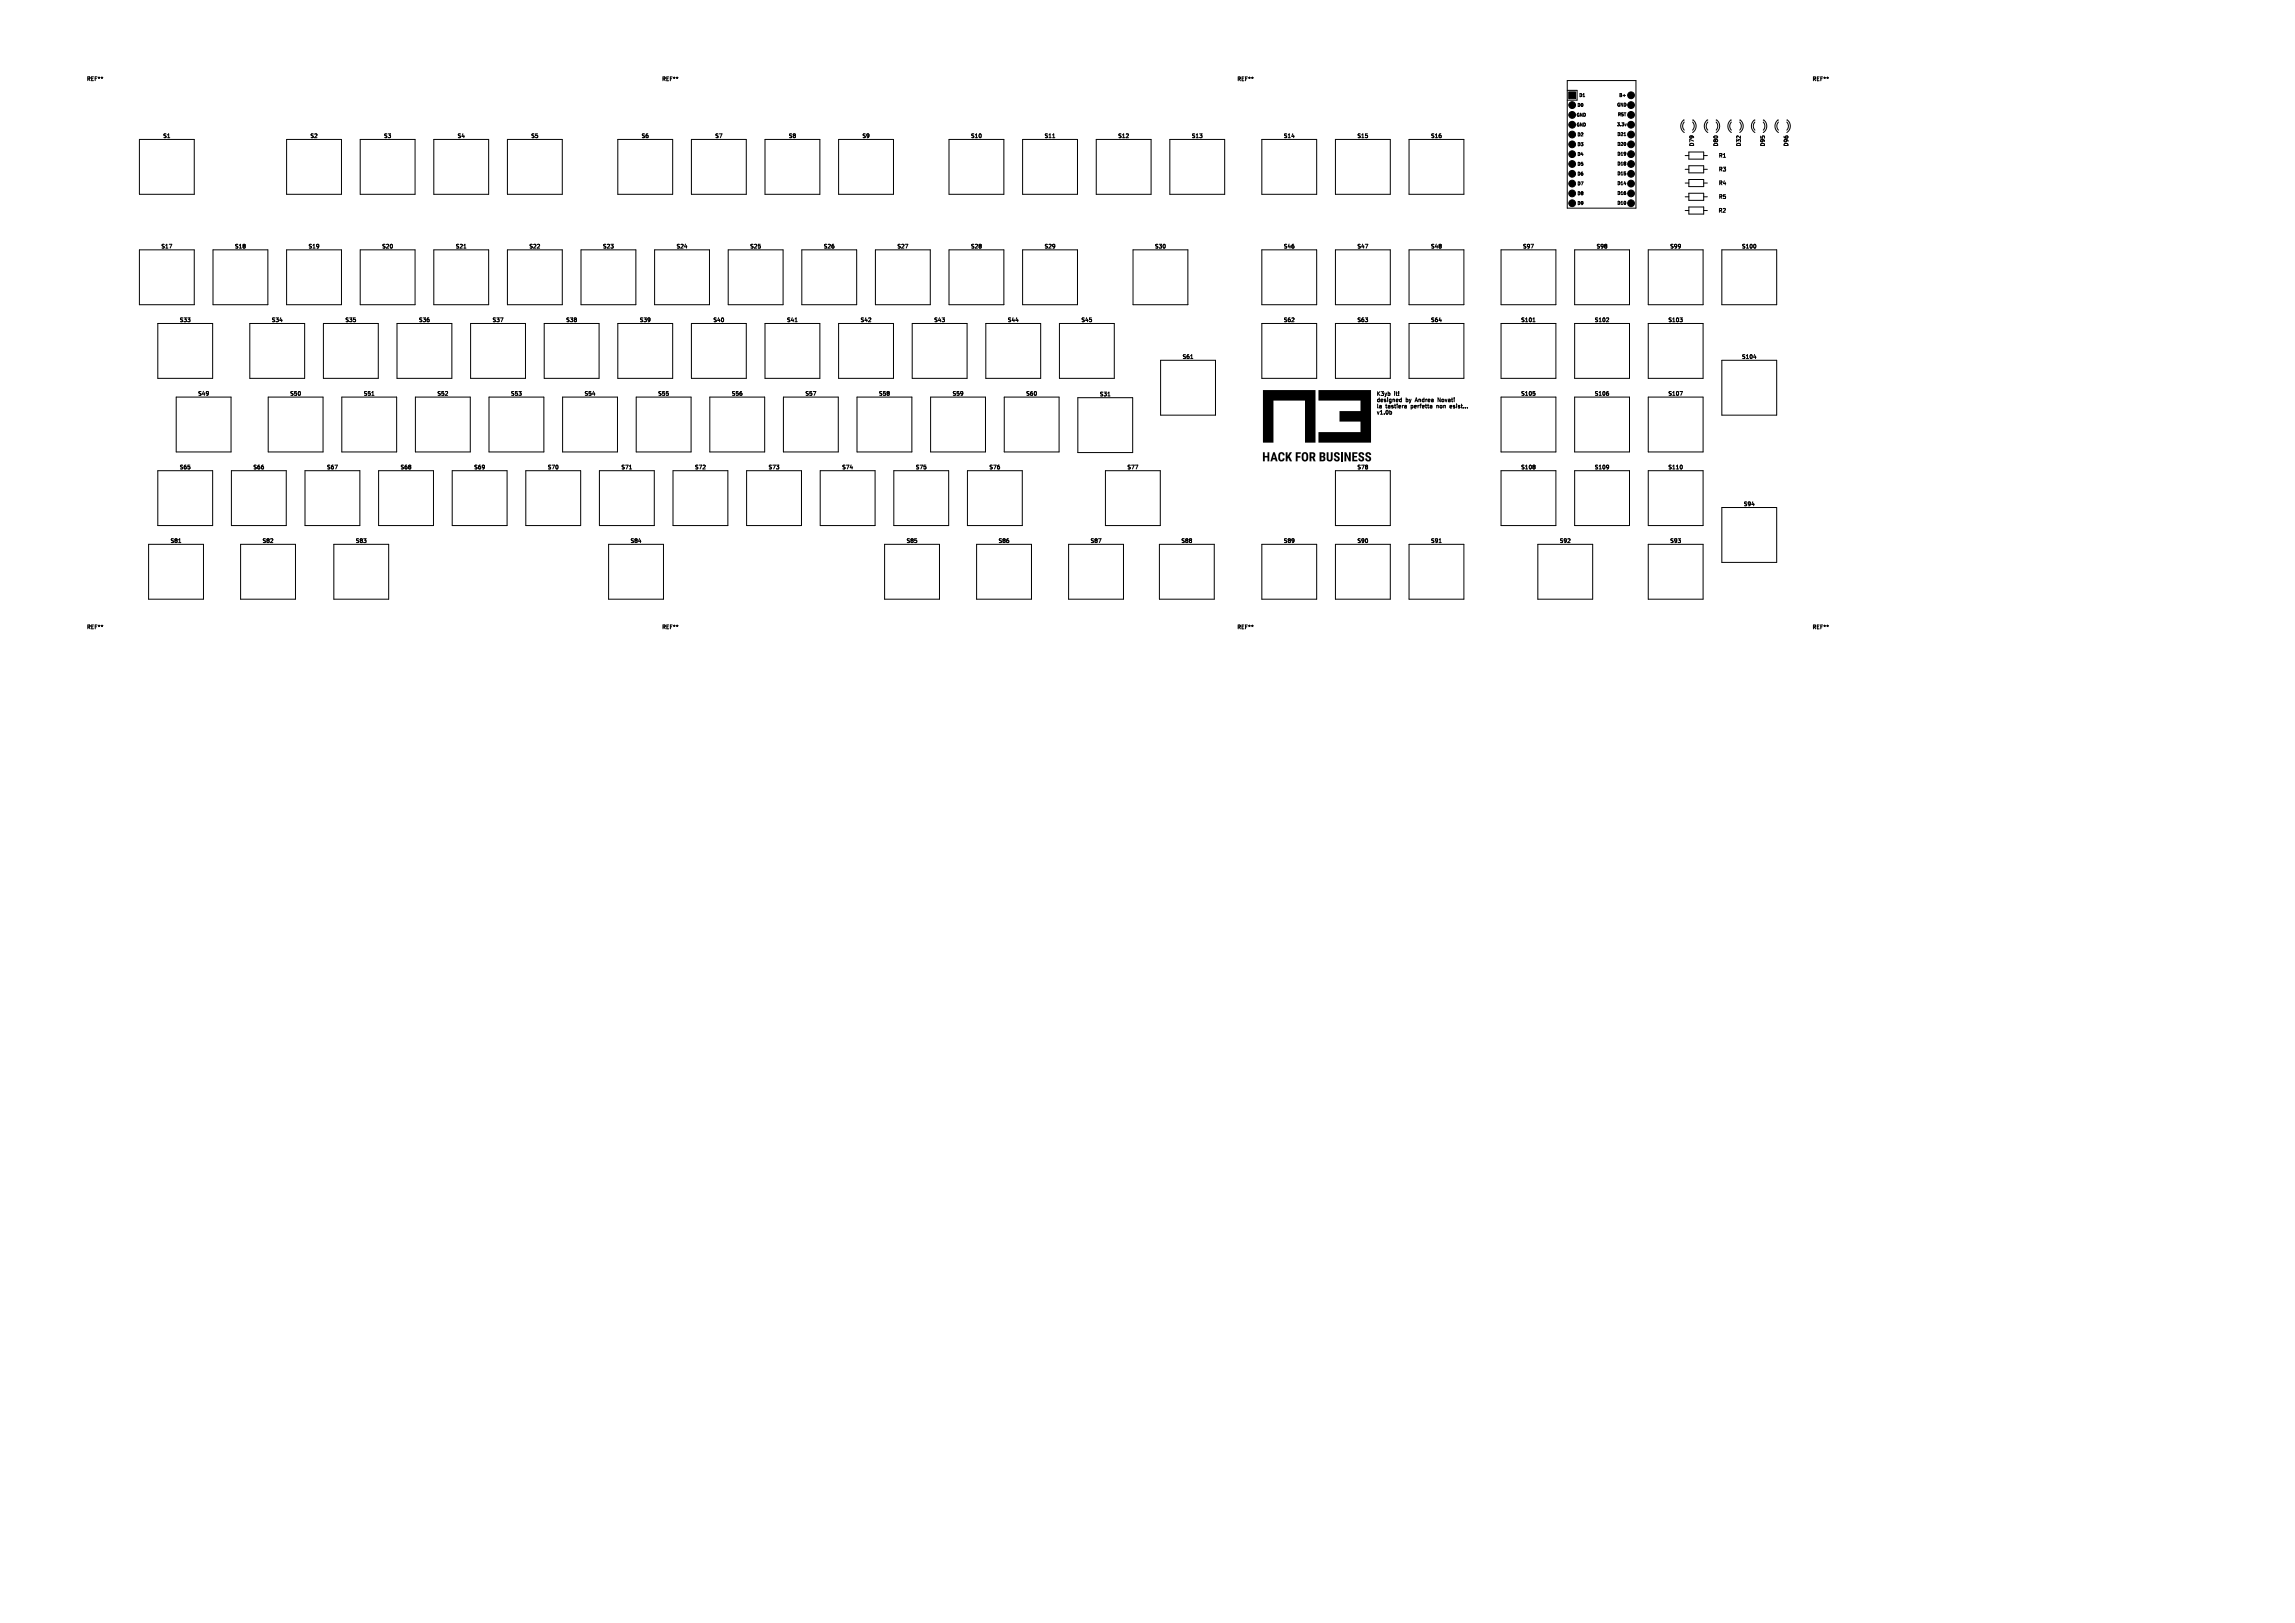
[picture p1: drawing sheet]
<svg xmlns="http://www.w3.org/2000/svg" width="594mm" height="420mm" viewBox="0 0 594 420" stroke-linecap="round" stroke-linejoin="round" font-family="sans-serif">
<defs><g id="words">
<g font-size="1.4">
<text x="22.4" y="21.2">REF**</text>
<text x="171.2" y="21.2">REF**</text>
<text x="320.1" y="21.2">REF**</text>
<text x="469" y="21.2">REF**</text>
<text x="42.1" y="35.9">S1</text>
<text x="80.2" y="35.9">S2</text>
<text x="99.3" y="35.9">S3</text>
<text x="118.3" y="35.9">S4</text>
<text x="137.4" y="35.9">S5</text>
<text x="165.9" y="35.9">S6</text>
<text x="185" y="35.9">S7</text>
<text x="204" y="35.9">S8</text>
<text x="223.1" y="35.9">S9</text>
<text x="251.2" y="35.9">S10</text>
<text x="270.2" y="35.9">S11</text>
<text x="289.3" y="35.9">S12</text>
<text x="308.3" y="35.9">S13</text>
<text x="332.1" y="35.9">S14</text>
<text x="351.2" y="35.9">S15</text>
<text x="370.2" y="35.9">S16</text>
<text x="438.6" y="38" transform="rotate(-90 438.6 38)">D79</text>
<text x="444.7" y="41">R1</text>
<text x="444.8" y="38" transform="rotate(-90 444.8 38)">D80</text>
<text x="450.7" y="38" transform="rotate(-90 450.7 38)">D32</text>
<text x="457" y="38" transform="rotate(-90 457 38)">D95</text>
<text x="463" y="38" transform="rotate(-90 463 38)">D96</text>
<text x="444.7" y="44.5">R3</text>
<text x="444.7" y="51.6">R5</text>
<text x="444.7" y="48.1">R4</text>
<text x="444.7" y="55.2">R2</text>
<text x="41.6" y="64.5">S17</text>
<text x="60.7" y="64.5">S18</text>
<text x="79.7" y="64.5">S19</text>
<text x="98.8" y="64.5">S20</text>
<text x="117.8" y="64.5">S21</text>
<text x="136.9" y="64.5">S22</text>
<text x="155.9" y="64.5">S23</text>
<text x="175" y="64.5">S24</text>
<text x="194" y="64.5">S25</text>
<text x="213.1" y="64.5">S26</text>
<text x="232.1" y="64.5">S27</text>
<text x="251.2" y="64.5">S28</text>
<text x="270.2" y="64.5">S29</text>
<text x="298.8" y="64.5">S30</text>
<text x="332.1" y="64.5">S46</text>
<text x="351.2" y="64.5">S47</text>
<text x="370.2" y="64.5">S48</text>
<text x="394.1" y="64.5">S97</text>
<text x="413.1" y="64.5">S98</text>
<text x="432.2" y="64.5">S99</text>
<text x="450.7" y="64.5">S100</text>
<text x="46.4" y="83.5">S33</text>
<text x="70.2" y="83.5">S34</text>
<text x="89.3" y="83.5">S35</text>
<text x="108.3" y="83.5">S36</text>
<text x="127.4" y="83.5">S37</text>
<text x="146.4" y="83.5">S38</text>
<text x="165.5" y="83.5">S39</text>
<text x="184.5" y="83.5">S40</text>
<text x="203.6" y="83.5">S41</text>
<text x="222.6" y="83.5">S42</text>
<text x="241.7" y="83.5">S43</text>
<text x="260.7" y="83.5">S44</text>
<text x="279.8" y="83.5">S45</text>
<text x="332.1" y="83.5">S62</text>
<text x="351.2" y="83.5">S63</text>
<text x="370.2" y="83.5">S64</text>
<text x="393.6" y="83.5">S101</text>
<text x="412.6" y="83.5">S102</text>
<text x="431.7" y="83.5">S103</text>
<text x="305.9" y="93.1">S61</text>
<text x="450.7" y="93.1">S104</text>
<text x="51.2" y="102.6">S49</text>
<text x="75" y="102.6">S50</text>
<text x="94" y="102.6">S51</text>
<text x="113.1" y="102.6">S52</text>
<text x="132.1" y="102.6">S53</text>
<text x="151.2" y="102.6">S54</text>
<text x="170.2" y="102.6">S55</text>
<text x="189.3" y="102.6">S56</text>
<text x="208.3" y="102.6">S57</text>
<text x="227.4" y="102.6">S58</text>
<text x="246.4" y="102.6">S59</text>
<text x="265.5" y="102.6">S60</text>
<text x="284.5" y="102.7">S31</text>
<text x="356.2" y="102.5">K3yb</text>
<text x="356.2" y="104.1">designed</text>
<text x="356.2" y="105.7">la</text>
<text x="356.2" y="107.3">v1.0b</text>
<text x="358.7" y="105.7">tastiera</text>
<text x="360.9" y="102.5">it!</text>
<text x="363.9" y="104.1">by</text>
<text x="365.4" y="105.7">perfetta</text>
<text x="366.5" y="104.1">Andrea</text>
<text x="372.3" y="105.7">non</text>
<text x="372.6" y="104.1">Novati</text>
<text x="376" y="105.7">esist...</text>
<text x="393.6" y="102.6">S105</text>
<text x="412.6" y="102.6">S106</text>
<text x="431.7" y="102.6">S107</text>
<text x="46.4" y="121.6">S65</text>
<text x="65.4" y="121.6">S66</text>
<text x="84.5" y="121.6">S67</text>
<text x="103.5" y="121.6">S68</text>
<text x="122.6" y="121.6">S69</text>
<text x="141.6" y="121.6">S70</text>
<text x="160.7" y="121.6">S71</text>
<text x="179.7" y="121.6">S72</text>
<text x="198.8" y="121.6">S73</text>
<text x="217.8" y="121.6">S74</text>
<text x="236.9" y="121.6">S75</text>
<text x="255.9" y="121.6">S76</text>
<text x="291.7" y="121.6">S77</text>
<text x="351.2" y="121.6">S78</text>
<text x="393.6" y="121.6">S108</text>
<text x="412.6" y="121.6">S109</text>
<text x="431.7" y="121.6">S110</text>
<text x="451.2" y="131.2">S94</text>
<text x="44" y="140.7">S81</text>
<text x="67.8" y="140.7">S82</text>
<text x="92" y="140.7">S83</text>
<text x="163.1" y="140.7">S84</text>
<text x="234.5" y="140.7">S85</text>
<text x="258.3" y="140.7">S86</text>
<text x="282.1" y="140.7">S87</text>
<text x="305.6" y="140.7">S88</text>
<text x="332.1" y="140.7">S89</text>
<text x="351.2" y="140.7">S90</text>
<text x="370.2" y="140.7">S91</text>
<text x="403.6" y="140.7">S92</text>
<text x="432.2" y="140.7">S93</text>
<text x="22.4" y="163">REF**</text>
<text x="171.2" y="163">REF**</text>
<text x="320.1" y="163">REF**</text>
<text x="469" y="163">REF**</text>
</g>
<g font-size="1.1">
<text x="408.1" y="27.8">D0</text>
<text x="408.6" y="25.3">D1</text>
<text x="418.4" y="27.7">GND</text>
<text x="419" y="25.3">B+</text>
<text x="407.9" y="30.4">GND</text>
<text x="407.9" y="32.9">GND</text>
<text x="408.1" y="35.4">D2</text>
<text x="418.4" y="32.8">3.3v</text>
<text x="418.5" y="35.4">D21</text>
<text x="418.6" y="30.3">RST</text>
<text x="408.1" y="40.5">D4</text>
<text x="408.1" y="38">D3</text>
<text x="418.5" y="40.4">D19</text>
<text x="418.5" y="37.9">D20</text>
<text x="408.1" y="45.6">D6</text>
<text x="408.1" y="43.1">D5</text>
<text x="418.5" y="43">D18</text>
<text x="418.5" y="45.5">D15</text>
<text x="408.1" y="50.7">D8</text>
<text x="408.1" y="48.1">D7</text>
<text x="408.1" y="53.2">D9</text>
<text x="418.5" y="50.6">D16</text>
<text x="418.5" y="48.1">D14</text>
<text x="418.5" y="53.1">D10</text>
</g>
</g></defs>
<g fill="#000">
<path d="M326.9 117h.5v1h.7v-1h.4v2.4h-.4v-1h-.7v1h-.5zM329.5 117h.5l.7 2.4h-.5l-.1-.5h-.7l-.1 .5h-.5l.3-.9h.9l-.3-.8-.2 .8h-.4zM331.1 117.2l.7-.2 .6 .4 .1 .4h-.5l-.3-.4-.4 .3 .2 1.3h.3l.2-.4h.5l-.4 .7-.7 .1-.5-.4-.1-1.1zM332.8 117h.4v1.1l.6-1.1h.6l-.7 1.1 .7 1.3h-.5l-.5-.9-.2 .2v.7h-.4zM335.4 117h1.3v.4h-.9v.6h.8v.4h-.8v1h-.4zM337.2 117.2l.8-.2 .5 .5 .1 1.2-.5 .7h-.7l-.4-.5-.1-.5h.5l.1 .5 .2 .1h.3l.1-.4v-.9l-.3-.3-.4 .2v.8h-.5zM338.9 117l1 .1 .4 .2 .1 .7-.3 .4 .4 1h-.5l-.3-.9h-.3v.9h-.5v-2h.5v.7h.4l.2-.3-.2-.4h-.9zM326.9 100.9h13.6v13.6h-2.7v-10.8h-8.2v10.8h-2.7zM341.5 117l1 .1 .4 .2 .1 .5-.3 .4 .3 .2v.4l-.2 .5-1.3 .1v-1h.5v.6h.4l.2-.3-.2-.3h-.9v-1h.5v.6h.4l.1-.2-.1-.4h-.9zM343.4 117h.5v1.8l.2 .2 .3-.2v-1.8h.5v1.8l-.3 .5-.7 .1-.4-.3zM345.4 117.2l.8-.2 .5 .4 .1 .3h-.5l-.3-.3-.2 .2 .9 .9v.5l-.3 .3-.7 .1-.4-.4-.1-.4h.5l.2 .4 .4-.2-.9-.8zM347.1 117h.5v2.4h-.5z"/>
<path d="M348 117h.4l.7 1.6v-1.6h.5v2.4h-.5l-.7-1.6v1.6h-.4zM350 117h1.3v.4h-.8v.6h.7v.4h-.7v.6h.8v.4h-1.3zM351.8 117.2l.7-.2 .5 .4 .1 .3h-.5l-.2-.3-.3 .2 .9 .9v.5l-.3 .3-.7 .1-.4-.4v-.4h.4l.3 .4 .3-.2-.1-.3-.8-.6zM353.6 117.2l.7-.2 .5 .4 .1 .3h-.5l-.2-.3-.3 .2 .9 .9v.5l-.3 .3-.7 .1-.4-.4-.1-.4h.5l.2 .4 .4-.2-.1-.3-.8-.6zM341.2 100.9h13.7v13.6h-13.7v-2.7h10.9v-2.7h-5.4v-2.7h5.4v-2.7h-10.9z"/>
</g>
<g fill="none" stroke="#000" stroke-width=".26">
<path d="M36.1 36.1h14.2v14.2h-14.2zM74.2 36.1h14.2v14.2h-14.2zM93.2 36.1h14.2v14.2h-14.2zM112.3 36.1h14.2v14.2h-14.2zM131.3 36.1h14.2v14.2h-14.2zM159.9 36.1h14.2v14.2h-14.2zM179 36.1h14.2v14.2h-14.2zM198 36.1h14.2v14.2h-14.2zM217.1 36.1h14.2v14.2h-14.2zM245.6 36.1h14.2v14.2h-14.2zM264.7 36.1h14.2v14.2h-14.2zM272.4 35.6h.6"/>
<path d="M283.7 36.1h14.2v14.2h-14.2zM302.8 36.1h14.2v14.2h-14.2zM326.6 36.1h14.2v14.2h-14.2zM345.6 36.1h14.2v14.2h-14.2zM364.7 36.1h14.2v14.2h-14.2zM405.6 20.8h17.8v33.1h-17.8zM405.6 23.4h2.6v2.5h-2.6M420.1 24.7h.6M420.3 35.1h.5M420.9 32l-.2 .6M435.9 31.6a1.5 1.5 0 0 0 0 2.1M435.9 31.1a1.88 1.88 0 0 0 0 3.2"/>
<path d="M437.1 39.3h3.9v1.9h-3.9zM438.1 31.1a1.89 1.89 0 0 1 0 3.2M438.1 31.6a1.5 1.5 0 0 1 0 2.1M442 31.6a1.5 1.5 0 0 0 0 2.1M442 31.1a1.88 1.88 0 0 0 0 3.2M444.2 31.1a1.89 1.89 0 0 1 0 3.2M444.2 31.6a1.5 1.5 0 0 1 0 2.1M448.1 31.6a1.5 1.5 0 0 0 0 2.1M448.1 31.1a1.88 1.88 0 0 0 0 3.2M450.3 31.1a1.88 1.88 0 0 1 0 3.2M450.3 31.6a1.5 1.5 0 0 1 0 2.1M454.2 31.6a1.5 1.5 0 0 0 0 2.1"/>
<path d="M454.2 31.1a1.88 1.88 0 0 0 0 3.2M456.4 31.1a1.88 1.88 0 0 1 0 3.2M456.4 31.6a1.5 1.5 0 0 1 0 2.1M460.3 31.6a1.5 1.5 0 0 0 0 2.1M460.3 31.1a1.88 1.88 0 0 0 0 3.2M462.5 31.1a1.89 1.89 0 0 1 0 3.2M462.5 31.6a1.5 1.5 0 0 1 0 2.1M436.2 43.8h.9M436.2 50.9h.9M436.2 47.4h.9M436.2 54.5h.9M436.2 40.3h.9"/>
<path d="M437.1 42.9h3.9v1.8h-3.9zM437.1 46.5h3.9v1.8h-3.9zM437.1 50h3.9v1.8h-3.9zM437.1 53.6h3.9v1.8h-3.9zM441 43.8h.9M441 50.9h.9M441 47.4h.9M441 54.5h.9M441 40.3h.9M36.1 64.7h14.2v14.2h-14.2zM55.1 64.7h14.2v14.2h-14.2zM74.2 64.7h14.2v14.2h-14.2z"/>
<path d="M93.2 64.7h14.2v14.2h-14.2zM112.3 64.7h14.2v14.2h-14.2zM120 64.2h.6M131.3 64.7h14.2v14.2h-14.2zM150.4 64.7h14.2v14.2h-14.2zM169.4 64.7h14.2v14.2h-14.2zM188.5 64.7h14.2v14.2h-14.2zM207.5 64.7h14.2v14.2h-14.2zM226.6 64.7h14.2v14.2h-14.2zM245.6 64.7h14.2v14.2h-14.2zM264.7 64.7h14.2v14.2h-14.2zM293.3 64.7h14.2v14.2h-14.2z"/>
<path d="M326.6 64.7h14.2v14.2h-14.2zM345.6 64.7h14.2v14.2h-14.2zM364.7 64.7h14.2v14.2h-14.2zM388.5 64.7h14.2v14.2h-14.2zM407.6 64.7h14.2v14.2h-14.2zM426.6 64.7h14.2v14.2h-14.2zM445.7 64.7h14.2v14.2h-14.2zM454.4 63.3v.8M40.8 83.7h14.2v14.2h-14.2zM64.7 83.7h14.2v14.2h-14.2zM83.7 83.7h14.2v14.2h-14.2zM102.8 83.7h14.2v14.2h-14.2z"/>
<path d="M121.8 83.7h14.2v14.2h-14.2zM140.9 83.7h14.2v14.2h-14.2zM159.9 83.7h14.2v14.2h-14.2zM179 83.7h14.2v14.2h-14.2zM198 83.7h14.2v14.2h-14.2zM205.8 83.3h.5M217.1 83.7h14.2v14.2h-14.2zM236.1 83.7h14.2v14.2h-14.2zM255.2 83.7h14.2v14.2h-14.2zM274.2 83.7h14.2v14.2h-14.2zM300.4 93.2h14.2v14.2h-14.2zM308.2 92.8h.5"/>
<path d="M326.6 83.7h14.2v14.2h-14.2zM345.6 83.7h14.2v14.2h-14.2zM364.7 83.7h14.2v14.2h-14.2zM388.5 83.7h14.2v14.2h-14.2zM396.7 83.3h.6M407.6 83.7h14.2v14.2h-14.2zM416.3 82.3v.4l-.6 .6h.7M426.6 83.7h14.2v14.2h-14.2zM434.8 82.3h.6l-.3 .3M435.3 82.7v.5M445.7 93.2h14.2v14.2h-14.2zM453.9 92.5h.6"/>
<path d="M45.6 102.8h14.2v14.2h-14.2zM69.4 102.8h14.2v14.2h-14.2zM88.5 102.8h14.2v14.2h-14.2zM96.2 102.3h.6M107.5 102.8h14.2v14.2h-14.2zM126.6 102.8h14.2v14.2h-14.2zM145.6 102.8h14.2v14.2h-14.2zM164.7 102.8h14.2v14.2h-14.2zM183.7 102.8h14.2v14.2h-14.2zM202.8 102.8h14.2v14.2h-14.2zM221.8 102.8h14.2v14.2h-14.2zM240.9 102.8h14.2v14.2h-14.2z"/>
<path d="M259.9 102.8h14.2v14.2h-14.2zM279 102.9h14.2v14.2h-14.2zM286.7 102.5h.6M360 106.5l.2 .2-.2 .5M362.3 103.9h.4M362.7 103v1M362.7 103.3l-.4 .1M363.7 104.9l.3 .2v.5M364 105.5l-.3 .1M364 105.1l-.3 .1M370.6 105v.6M370.6 105.5l-.1 .1"/>
<path d="M370.6 105.1l-.1 .1M371.9 104.9v.7M371.9 105h.1M372.2 104v-1l.6 1M375.6 104.9l-.3 .2v.4l.3 .1M375.8 105.1l-.5 .1M388.5 102.8h14.2v14.2h-14.2zM396.8 101.3h.5M397.2 101.7v.6M407.6 102.8h14.2v14.2h-14.2zM416.3 101.7v.6M426.6 102.8h14.2v14.2h-14.2z"/>
<path d="M434.8 101.3h.7l-.5 1M40.8 121.8h14.2v14.2h-14.2zM59.9 121.8h14.2v14.2h-14.2zM78.9 121.8h14.2v14.2h-14.2zM98 121.8h14.2v14.2h-14.2zM117 121.8h14.2v14.2h-14.2zM136.1 121.8h14.2v14.2h-14.2zM155.1 121.8h14.2v14.2h-14.2zM162.9 121.4h.6M174.2 121.8h14.2v14.2h-14.2zM193.2 121.8h14.2v14.2h-14.2zM212.3 121.8h14.2v14.2h-14.2z"/>
<path d="M231.3 121.8h14.2v14.2h-14.2zM250.4 121.8h14.2v14.2h-14.2zM286.1 121.8h14.2v14.2h-14.2zM345.6 121.8h14.2v14.2h-14.2zM388.5 121.8h14.2v14.2h-14.2zM397.2 120.4v.3M397.2 120.8v.5M407.6 121.8h14.2v14.2h-14.2zM416.3 120.4l-.1 .9M416.4 120.8l-.1 .1M426.6 121.8h14.2v14.2h-14.2zM435.3 120.5v.8"/>
<path d="M445.7 131.3h14.2v14.2h-14.2zM38.5 140.9h14.2v14.2h-14.2zM46.2 140.4h.6M62.3 140.9h14.2v14.2h-14.2zM86.4 140.9h14.2v14.2h-14.2zM157.5 140.9h14.2v14.2h-14.2zM229 140.9h14.2v14.2h-14.2zM252.8 140.9h14.2v14.2h-14.2zM276.6 140.9h14.2v14.2h-14.2zM300.1 140.9h14.2v14.2h-14.2zM326.6 140.9h14.2v14.2h-14.2zM345.6 140.9h14.2v14.2h-14.2z"/>
<path d="M364.7 140.9h14.2v14.2h-14.2zM372.5 140.4h.5M398 140.9h14.2v14.2h-14.2zM426.6 140.9h14.2v14.2h-14.2z"/>
</g>
<g fill="#000" stroke="#000" stroke-width=".26">
<path d="M406 23.8h1.8v1.7h-1.8z"/>
<circle cx="406.9" cy="39.9" r=".88"/>
<circle cx="406.9" cy="34.8" r=".88"/>
<circle cx="406.9" cy="27.2" r=".88"/>
<circle cx="406.9" cy="29.7" r=".88"/>
<circle cx="406.9" cy="32.3" r=".88"/>
<circle cx="406.9" cy="37.4" r=".88"/>
<circle cx="422.2" cy="32.3" r=".88"/>
<circle cx="422.2" cy="27.2" r=".88"/>
<circle cx="422.2" cy="39.9" r=".88"/>
<circle cx="422.2" cy="37.4" r=".88"/>
<circle cx="422.2" cy="24.7" r=".88"/>
<circle cx="422.2" cy="34.8" r=".88"/>
<circle cx="422.2" cy="29.7" r=".88"/>
<circle cx="406.9" cy="45" r=".88"/>
<circle cx="406.9" cy="50.1" r=".88"/>
<circle cx="406.9" cy="47.5" r=".88"/>
<circle cx="406.9" cy="52.6" r=".88"/>
<circle cx="406.9" cy="42.4" r=".88"/>
<circle cx="422.2" cy="42.4" r=".88"/>
<circle cx="422.2" cy="52.6" r=".88"/>
<circle cx="422.2" cy="47.5" r=".88"/>
<circle cx="422.2" cy="50.1" r=".88"/>
<circle cx="422.2" cy="45" r=".88"/>
</g>
<use href="#words"/>
</svg>
